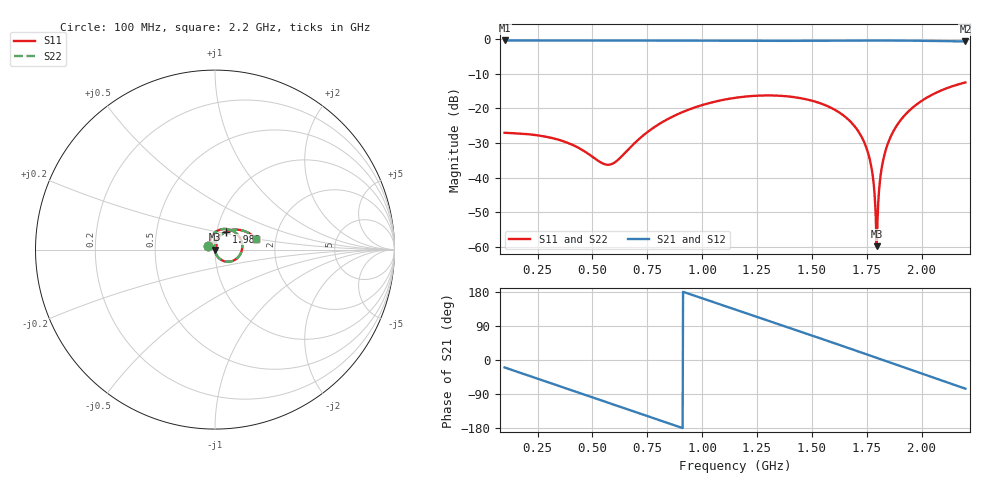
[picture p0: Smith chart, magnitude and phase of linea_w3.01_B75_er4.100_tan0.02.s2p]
! Chirptenna · simulación 3D de una microstrip de dos puertos (S12 = S21, S22 = S11 por simetría)
# HZ S RI R 50
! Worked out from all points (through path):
!   1101 points, 100 MHz to 2.2 GHz, reference 50 ohm
!   highest |S21| = -0.30 dB at 100 MHz (marker M1); lowest = -0.6 dB at 2.2 GHz (marker M2)
!   group delay of S21, straight-line fit = 549 ps
!   lowest |S11| = -59.9 dB at 1.795 GHz (marker M3), VSWR 1.00, Z = 49.9 - j0.036 ohm
!   |S11| at or under -10 dB: start of sweep to end of sweep
!   |S22| runs from -59.9 to -12.5 dB; largest |S21 - S12| = 0
!   S11 on the Smith chart (normalised r, x): 100 MHz: 0.93, +0.04; 1.982 GHz: 1.11, +0.22; 2.2 GHz: 1.59, +0.19
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1e8  -0.0384 0.0225  0.9101 -0.3258  0.9101 -0.3258  -0.0384 0.0225
2.909091e8  -0.00482 0.0385  0.5224 -0.8125  0.5224 -0.8125  -0.00482 0.0385
4.512727e8  0.00909 0.0237  0.0199 -0.9653  0.0199 -0.9653  0.00909 0.0237
5.849091e8  -0.00255 0.0153  -0.4102 -0.8739  -0.4102 -0.8739  -0.00255 0.0153
8.006364e8  -0.0242 0.0533  -0.8922 -0.3649  -0.8922 -0.3649  -0.0242 0.0533
9.705455e8  0.0113 0.1039  -0.9416 0.1888  -0.9416 0.1888  0.0113 0.1039
1.15e9  0.0956 0.1058  -0.6557 0.6946  -0.6557 0.6946  0.0956 0.1058
1.327545e9  0.1508 0.0318  -0.1421 0.942  -0.1421 0.942  0.1508 0.0318
1.501273e9  0.1187 -0.0516  0.4116 0.8624  0.4116 0.8624  0.1187 -0.0516
1.634909e9  0.0524 -0.0649  0.7569 0.5912  0.7569 0.5912  0.0524 -0.0649
1.722727e9  0.0142 -0.0386  0.9027 0.3356  0.9027 0.3356  0.0142 -0.0386
1.766636e9  0.00269 -0.0167  0.9444 0.1929  0.9444 0.1929  0.00269 -0.0167
1.78e9  0.000583 -0.00925  0.9525 0.1482  0.9525 0.1482  0.000583 -0.00925
1.789545e9  -0.000486 -0.00373  0.957 0.1161  0.957 0.1161  -0.000486 -0.00373
1.795273e9  -0.000948 -0.000361  0.9592 0.0967  0.9592 0.0967  -0.000948 -0.000361
1.802909e9  -0.00135 0.00419  0.9615 0.0708  0.9615 0.0708  -0.00135 0.00419
1.810545e9  -0.0015 0.00881  0.963 0.0448  0.963 0.0448  -0.0015 0.00881
1.820091e9  -0.00134 0.0146  0.9639 0.0123  0.9639 0.0123  -0.00134 0.0146
1.850636e9  0.00191 0.0335  0.9592 -0.0916  0.9592 -0.0916  0.00191 0.0335
1.904091e9  0.0176 0.065  0.9233 -0.2699  0.9233 -0.2699  0.0176 0.065
1.982364e9  0.0617 0.1  0.8105 -0.5094  0.8105 -0.5094  0.0617 0.1
2.2e9  0.2312 0.0579  0.2326 -0.9057  0.2326 -0.9057  0.2312 0.0579
